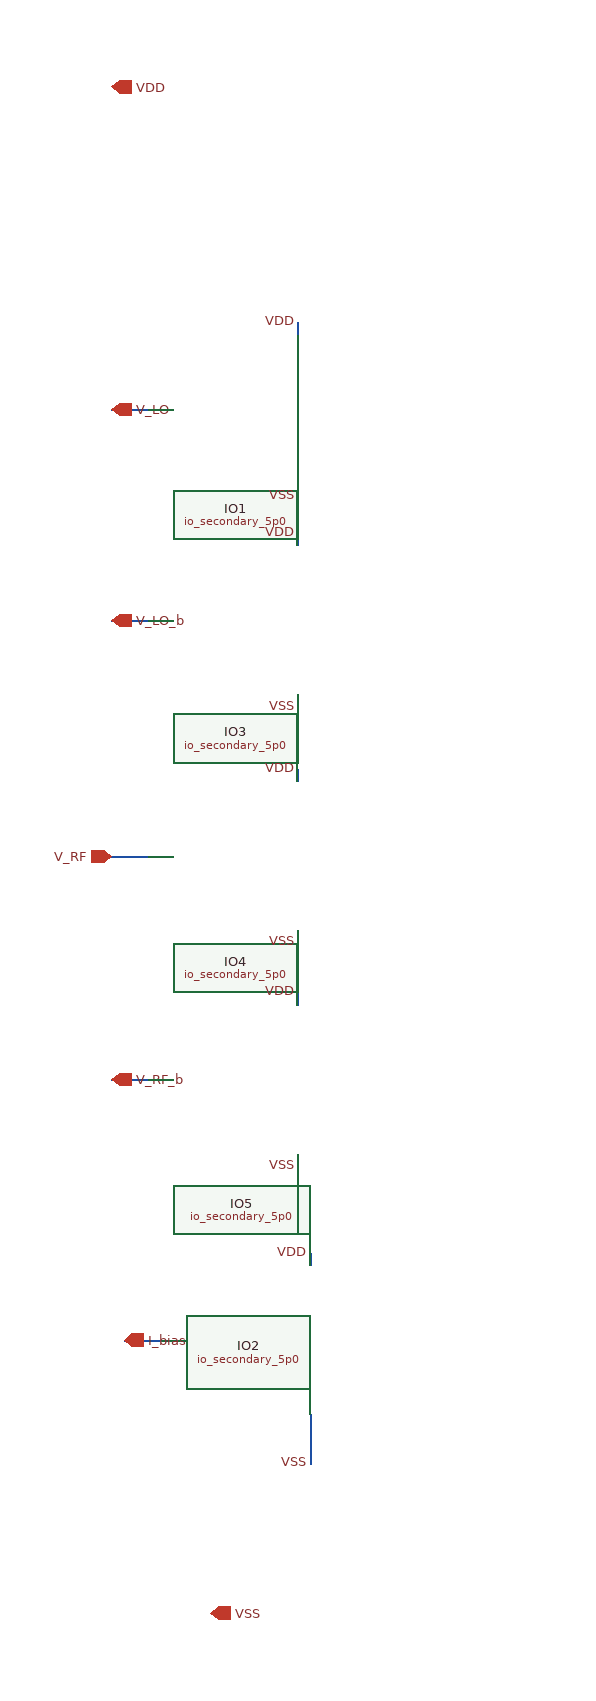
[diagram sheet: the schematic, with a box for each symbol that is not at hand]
v {xschem version=3.4.5 file_version=1.2
}
G {}
K {}
V {}
S {}
E {}
N 1140 -870 1140 -840 {
lab=VSS}
N 1140 -880 1140 -870 {
lab=VSS}
N 980 -1690 1010 -1690 {
lab=V_LO}
N 980 -1520 1010 -1520 {
lab=V_LO_b}
N 980 -1330 1010 -1330 {
lab=V_RF}
N 980 -1150 1010 -1150 {
lab=V_RF_b}
N 1140 -1010 1140 -1000 {
lab=VDD}
N 1130 -1220 1130 -1210 {
lab=VDD}
N 1130 -1400 1130 -1390 {
lab=VDD}
N 1130 -1590 1130 -1580 {
lab=VDD}
N 1130 -1760 1130 -1750 {
lab=VDD}
N 1130 -1090 1130 -1080 {
lab=VSS}
N 1130 -1270 1130 -1260 {
lab=VSS}
N 1130 -1460 1130 -1450 {
lab=VSS}
N 1130 -1630 1130 -1620 {
lab=VSS}
N 990 -940 1020 -940 {
lab=I_bias}
C {ipin.sym} 980 -1690 2 1 {name=p1 lab=V_LO}
C {ipin.sym} 980 -1520 2 1 {name=p2 lab=V_LO_b
}
C {ipin.sym} 980 -1330 0 0 {name=p3 lab=V_RF}
C {ipin.sym} 980 -1150 2 1 {name=p4 lab=V_RF_b
}
C {/home/vasil/Downloads/SSCS_PICO_2025/src/design_padring/Chipathon2025_pads/xschem/symbols/io_secondary_5p0/io_secondary_5p0.sym} 1210 -1610 0 1 {name=IO1
spiceprefix=X
}
C {/home/vasil/Downloads/SSCS_PICO_2025/src/design_padring/Chipathon2025_pads/xschem/symbols/io_secondary_5p0/io_secondary_5p0.sym} 1220 -860 0 1 {name=IO2
spiceprefix=X
}
C {/home/vasil/Downloads/SSCS_PICO_2025/src/design_padring/Chipathon2025_pads/xschem/symbols/io_secondary_5p0/io_secondary_5p0.sym} 1210 -1440 0 1 {name=IO3
spiceprefix=X
}
C {/home/vasil/Downloads/SSCS_PICO_2025/src/design_padring/Chipathon2025_pads/xschem/symbols/io_secondary_5p0/io_secondary_5p0.sym} 1210 -1250 0 1 {name=IO4
spiceprefix=X
}
C {/home/vasil/Downloads/SSCS_PICO_2025/src/design_padring/Chipathon2025_pads/xschem/symbols/io_secondary_5p0/io_secondary_5p0.sym} 1210 -1070 0 1 {name=IO5
spiceprefix=X
}
C {lab_pin.sym} 1140 -1010 0 0 {name=p6 sig_type=std_logic lab=VDD}
C {lab_pin.sym} 1130 -1220 0 0 {name=p12 sig_type=std_logic lab=VDD}
C {lab_pin.sym} 1130 -1400 0 0 {name=p13 sig_type=std_logic lab=VDD}
C {lab_pin.sym} 1130 -1590 0 0 {name=p14 sig_type=std_logic lab=VDD}
C {lab_pin.sym} 1130 -1760 0 0 {name=p16 sig_type=std_logic lab=VDD}
C {ipin.sym} 990 -940 2 1 {name=p18 lab=I_bias
}
C {ipin.sym} 1060 -720 2 1 {name=p8 lab=VSS
}
C {ipin.sym} 980 -1950 2 1 {name=p9 lab=VDD
}
C {lab_pin.sym} 1140 -840 0 0 {name=p10 sig_type=std_logic lab=VSS}
C {lab_pin.sym} 1130 -1080 0 0 {name=p19 sig_type=std_logic lab=VSS}
C {lab_pin.sym} 1130 -1260 0 0 {name=p20 sig_type=std_logic lab=VSS}
C {lab_pin.sym} 1130 -1450 0 0 {name=p21 sig_type=std_logic lab=VSS}
C {lab_pin.sym} 1130 -1620 0 0 {name=p22 sig_type=std_logic lab=VSS}
